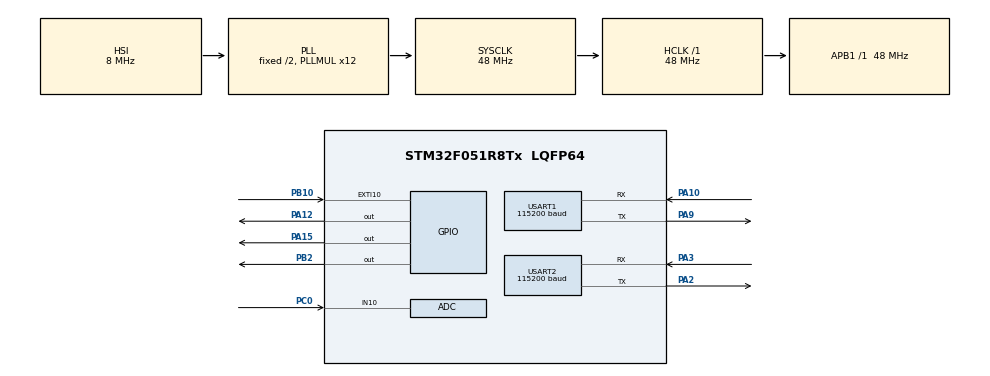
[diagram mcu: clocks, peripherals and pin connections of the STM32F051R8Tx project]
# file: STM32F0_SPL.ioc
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Mcu.Family=STM32F0
Mcu.Name=STM32F051R8Tx
Mcu.Package=LQFP64
NVIC.ADC1_COMP_IRQn=true\:0\:0\:false\:false\:true
NVIC.EXTI4_15_IRQn=true\:0\:0\:false\:false\:true
NVIC.TIM3_IRQn=true\:0\:0\:false\:false\:true
NVIC.USART1_IRQn=true\:0\:0\:false\:false\:true
NVIC.USART2_IRQn=true\:0\:0\:false\:false\:true
PA10.Mode=Asynchronous
PA10.Signal=USART1_RX
PA12.PinState=GPIO_PIN_SET
PA12.Signal=GPIO_Output
PA13.Mode=Serial-WireDebug
PA13.Signal=SYS_SWDIO
PA14.Mode=Serial-WireDebug
PA14.Signal=SYS_SWCLK
PA15.PinState=GPIO_PIN_SET
PA15.Signal=GPIO_Output
PA2.Mode=Asynchronous
PA2.Signal=USART2_TX
PA3.Mode=Asynchronous
PA3.Signal=USART2_RX
PA9.Mode=Asynchronous
PA9.Signal=USART1_TX
PB10.GPIO_ModeDefaultEXTI=GPIO_MODE_IT_FALLING
PB10.Signal=GPXTI10
PB2.Signal=GPIO_Output
PC0.Mode=IN10
PC0.Signal=ADC_IN10
ProjectManager.HeapSize=0x200
ProjectManager.StackSize=0x400
ProjectManager.TargetToolchain=MDK-ARM V5
RCC.AHBFreq_Value=48000000
RCC.APB1Freq_Value=48000000
RCC.APB1TimFreq_Value=48000000
RCC.HCLKFreq_Value=48000000
RCC.PLLMUL=RCC_PLL_MUL12
RCC.SYSCLKFreq_VALUE=48000000
RCC.SYSCLKSource=RCC_SYSCLKSOURCE_PLLCLK
USART1.BaudRate=115200
USART2.BaudRate=115200
VP_TIM3_VS_ClockSourceINT.Mode=Internal
board=STM32F0_SPL

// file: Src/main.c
/**
  ******************************************************************************
  * File Name          : main.c
  * Description        : Main program body
  ******************************************************************************
  *
  * COPYRIGHT(c) 2016 STMicroelectronics
  *
  * Redistribution and use in source and binary forms, with or without modification,
  * are permitted provided that the following conditions are met:
  *   1. Redistributions of source code must retain the above copyright notice,
  *      this list of conditions and the following disclaimer.
  *   2. Redistributions in binary form must reproduce the above copyright notice,
  *      this list of conditions and the following disclaimer in the documentation
  *      and/or other materials provided with the distribution.
  *   3. Neither the name of STMicroelectronics nor the names of its contributors
  *      may be used to endorse or promote products derived from this software
  *      without specific prior written permission.
  *
  * THIS SOFTWARE IS PROVIDED BY THE COPYRIGHT HOLDERS AND CONTRIBUTORS "AS IS"
  * AND ANY EXPRESS OR IMPLIED WARRANTIES, INCLUDING, BUT NOT LIMITED TO, THE
  * IMPLIED WARRANTIES OF MERCHANTABILITY AND FITNESS FOR A PARTICULAR PURPOSE ARE
  * DISCLAIMED. IN NO EVENT SHALL THE COPYRIGHT HOLDER OR CONTRIBUTORS BE LIABLE
  * FOR ANY DIRECT, INDIRECT, INCIDENTAL, SPECIAL, EXEMPLARY, OR CONSEQUENTIAL
  * DAMAGES (INCLUDING, BUT NOT LIMITED TO, PROCUREMENT OF SUBSTITUTE GOODS OR
  * SERVICES; LOSS OF USE, DATA, OR PROFITS; OR BUSINESS INTERRUPTION) HOWEVER
  * CAUSED AND ON ANY THEORY OF LIABILITY, WHETHER IN CONTRACT, STRICT LIABILITY,
  * OR TORT (INCLUDING NEGLIGENCE OR OTHERWISE) ARISING IN ANY WAY OUT OF THE USE
  * OF THIS SOFTWARE, EVEN IF ADVISED OF THE POSSIBILITY OF SUCH DAMAGE.
  *
  ******************************************************************************
  */
//#include "stm32f0xx_hal.h"
#include "main.h"
#include "print_debug.h"
#include "gsm.h"

#include "network.h"

ADC_HandleTypeDef hadc;

TIM_HandleTypeDef htim3;

UART_HandleTypeDef huart1;
UART_HandleTypeDef huart2;

/* USER CODE BEGIN PV */
/* Private variables ---------------------------------------------------------*/
data_t data_gsm, data_debug;
recv_uart_t recv_uart_1,recv_uart_2;
/* USER CODE END PV */

void SystemClock_Config(void);
static void MX_GPIO_Init(void);
static void MX_ADC_Init(void);
static void MX_TIM3_Init(void);
static void MX_USART1_UART_Init(void);
static void MX_USART2_UART_Init(void);

extern int FlagSendAlarm;

/* USER CODE BEGIN PFP */
/* Private function prototypes -----------------------------------------------*/

/* USER CODE END PFP */

int main(void)
{

  /* USER CODE BEGIN 1 */
	int8_t ret = 0;
	uint16_t idx_r = 0;
	char *tok = NULL;
	char *tok_buf = NULL;
  /* USER CODE END 1 */

  /* MCU Configuration----------------------------------------------------------*/

  /* Reset of all peripherals, Initializes the Flash interface and the Systick. */
  HAL_Init();

  /* Configure the system clock */
  SystemClock_Config();

  /* Initialize all configured peripherals */
  MX_GPIO_Init();
  MX_ADC_Init();
  MX_TIM3_Init();
  MX_USART1_UART_Init();
  MX_USART2_UART_Init();

	__HAL_UART_ENABLE_IT(&huart1,UART_IT_RXNE);
	__HAL_UART_ENABLE_IT(&huart2,UART_IT_RXNE);
	memset(&recv_uart_1,0,sizeof(recv_uart_t));
	memset(&recv_uart_2,0,sizeof(recv_uart_t));
	print_init(&huart2);

  /* Infinite loop */
  /* USER CODE BEGIN WHILE */

	memset(&data_gsm,0,sizeof(data_t));
	memset(&data_debug,0,sizeof(data_t));

//	HAL_GPIO_WritePin(GPIOC,GPIO_PIN_6,GPIO_PIN_SET);
//	HAL_Delay(1000);
//	HAL_GPIO_WritePin(GPIOC,GPIO_PIN_6,GPIO_PIN_RESET);
//	HAL_Delay(500);
//
//	HAL_GPIO_WritePin(GPIOA,GPIO_PIN_15,GPIO_PIN_RESET);
//	HAL_Delay(1000);
//	HAL_GPIO_WritePin(GPIOA,GPIO_PIN_12,GPIO_PIN_RESET);
//	HAL_Delay(1000);
//	HAL_GPIO_WritePin(GPIOA,GPIO_PIN_12,GPIO_PIN_SET);
//	HAL_Delay(1000);
//	HAL_GPIO_WritePin(GPIOA,GPIO_PIN_11,GPIO_PIN_RESET);
//	HAL_Delay(1000);
//
//	HAL_GPIO_WritePin(GPIOC,GPIO_PIN_6,GPIO_PIN_SET);
//	HAL_Delay(1000);
//	HAL_GPIO_WritePin(GPIOC,GPIO_PIN_6,GPIO_PIN_RESET);
//	HAL_Delay(500);

//	while(1){
//
//		ret = gsm_read(data_gsm.value,&data_gsm.length);
//		if(ret){
//			if(data_gsm.length > 0){
//				print_payload(0,data_gsm.value,data_gsm.length);
//			}
//		}
//		ret = uart2_read(data_debug.value,&data_debug.length,255);
//		if(ret){
//			if(data_debug.length > 0){
//				//print_payload(0,data_debug.value,data_debug.length);
//				gsm_write(data_debug.value,data_debug.length);
//			}
//		}
//	}
//
//	HAL_UART_Transmit(&huart1,(uint8_t*)"AT+CGPSPWR=1\r\n",14,100);
//	HAL_Delay(1000);
//	ret = gsm_read(data_gsm.value,&data_gsm.length);
//	if(ret){
//		if(data_gsm.length > 0){
//			HAL_UART_Transmit(&huart2,data_gsm.value,data_gsm.length,100);
//			print_payload(0,data_gsm.value,data_gsm.length);
//		}
//	}
//
//	HAL_UART_Transmit(&huart1,(uint8_t*)"AT+CGPSRST=0\r\n",14,100);
//	HAL_Delay(1000);
//	if(ret){
//		if(data_gsm.length > 0){
//			print_payload(0,data_gsm.value,data_gsm.length);
//		}
//	}
//
//	HAL_UART_Transmit(&huart1,(uint8_t*)"AT+CGPSSTATUS?\r\n",16,100);
//	HAL_Delay(1000);
//	if(ret){
//		if(data_gsm.length > 0){
//			print_payload(0,data_gsm.value,data_gsm.length);
//		}
//	}
	Power_On();
//	//HAL_Delay(10000);
	//Start_GPS();
	net_ptc(NET_MQTT_PTC);

	//power_onGPS();
	HAL_Delay(2000);

  while (1)
  {
  /* USER CODE END WHILE */

		HAL_Delay(1000);
		net_run();

		//read_sensor();

  }

}

void Power_On(void)
{
	uint8_t ret =0;
	print_debug(0,"program startup...\n");
	HAL_GPIO_WritePin(GPIOA,GPIO_PIN_15,GPIO_PIN_RESET);
	HAL_Delay(1000);
	HAL_GPIO_WritePin(GPIOA,GPIO_PIN_12,GPIO_PIN_RESET);
	HAL_Delay(3000);
	HAL_GPIO_WritePin(GPIOA,GPIO_PIN_12,GPIO_PIN_SET);

	HAL_GPIO_WritePin(GPIOA,GPIO_PIN_11,GPIO_PIN_RESET);

	HAL_Delay(5000);

	print_debug(0,"[GSM] AT \n");
	SsendATcommand((uint8_t*)"ATE0\r\n",4,(uint8_t*)"\r\nOK\r\n",6,500);
	while(ret==0)
	{
		ret = SsendATcommand((uint8_t*)"AT\r\n",4,(uint8_t*)"\r\nOK\r\n",6,500);
	}
	print_debug(0,"[INFO] GSM ON.\r\n");

	print_debug(0,"(Powers GPS)AT+CGPSPWR=1\r\n");
	SsendATcommand((uint8_t*)"AT+CGPSPWR=1\r\n",14,(uint8_t*)"\r\nOK\r\n",6,500);
	HAL_Delay(2000);

	print_debug(0,"(Set Reset mode)AT+CGPSRST=0\r\n");
	SsendATcommand((uint8_t*)"AT+CGPSRST=0\r\n",14,(uint8_t*)"\r\nOK\r\n",6,500);

	ReadBett();

	//ret = 0;
	while(1)
	{
		print_debug(0,"(STATUS)AT+CGPSSTATUS?\r\n");
		if(SsendATcommand((uint8_t*)"AT+CGPSSTATUS?\r\n",16,(uint8_t*)"\r\n+CGPSSTATUS: Location 2D Fix\r\n",32,5000))
		{
			break;
		}
		if(SsendATcommand((uint8_t*)"AT+CGPSSTATUS?\r\n",16,(uint8_t*)"\r\n+CGPSSTATUS: Location 3D Fix\r\n",32,5000))
		{
			break;
		}
	}

	while (SsendATcommand((uint8_t*)"AT+CREG?\r\n",14,(uint8_t*)"\r\n+CREG: 0,1",12,2000) == 0);

	print_debug(0,"[GSM] SET GPRS.\r\n");
	SsendATcommand((uint8_t*)"AT+SAPBR=3,1,\"Contype\",\"GPRS\"\r\n",31,(uint8_t*)"\r\nOK\r\n",6,500);
	print_debug(0,"[GSM] SET APN.\r\n");
	SsendATcommand((uint8_t*)"AT+SAPBR=3,1,\"APN\",\"www.dtac.co.th\"\r\n",37,(uint8_t*)"\r\nOK\r\n",6,500);

	 // gets the GPRS bearer
	print_debug(0,"[GSM] GET GPRS.\r\n");
	while (SsendATcommand((uint8_t*)"AT+SAPBR=1,1\r\n",14,(uint8_t*)"\r\nOK\r\n",6,3000) == 0)
	{
			//print_debug(0,"[GSM] ERROR\r\n");
			HAL_Delay(5000);
	}

}

int SsendATcommand(uint8_t* ATcommand,uint16_t lenAT,uint8_t* Ret,uint16_t lenRet,int Time)
{
	int ret =0;
	int C = 0;
	ret = gsm_write((uint8_t*)ATcommand,lenAT);
	HAL_Delay(Time);
	ret = gsm_read(data_gsm.value,&data_gsm.length);
	if(ret == 1)
	{
		if(data_gsm.length > 0){
			print_payload(0,data_gsm.value,data_gsm.length);
			//print_debug(0,"(RETURN GSM) %s  :",data_gsm.value);
			if(strncmp((char*)data_gsm.value,(char*)Ret,lenRet)==0){
				C = 1;
				//print_debug(0,"[INFO] GSM ON.\r\n");
				//print_debug(0,"[INFO] GSM ON.\r\n");
				//break;
			}
		}
	}

	return C;
}

/** System Clock Configuration
*/
void SystemClock_Config(void)
{

  RCC_OscInitTypeDef RCC_OscInitStruct;
  RCC_ClkInitTypeDef RCC_ClkInitStruct;
  RCC_PeriphCLKInitTypeDef PeriphClkInit;

  RCC_OscInitStruct.OscillatorType = RCC_OSCILLATORTYPE_HSI|RCC_OSCILLATORTYPE_HSI14;
  RCC_OscInitStruct.HSIState = RCC_HSI_ON;
  RCC_OscInitStruct.HSI14State = RCC_HSI14_ON;
  RCC_OscInitStruct.HSICalibrationValue = 16;
  RCC_OscInitStruct.HSI14CalibrationValue = 16;
  RCC_OscInitStruct.PLL.PLLState = RCC_PLL_ON;
  RCC_OscInitStruct.PLL.PLLSource = RCC_PLLSOURCE_HSI;
  RCC_OscInitStruct.PLL.PLLMUL = RCC_PLL_MUL12;
  RCC_OscInitStruct.PLL.PREDIV = RCC_PREDIV_DIV1;
  HAL_RCC_OscConfig(&RCC_OscInitStruct);

  RCC_ClkInitStruct.ClockType = RCC_CLOCKTYPE_HCLK|RCC_CLOCKTYPE_SYSCLK
                              |RCC_CLOCKTYPE_PCLK1;
  RCC_ClkInitStruct.SYSCLKSource = RCC_SYSCLKSOURCE_PLLCLK;
  RCC_ClkInitStruct.AHBCLKDivider = RCC_SYSCLK_DIV1;
  RCC_ClkInitStruct.APB1CLKDivider = RCC_HCLK_DIV1;
  HAL_RCC_ClockConfig(&RCC_ClkInitStruct, FLASH_LATENCY_1);

  PeriphClkInit.PeriphClockSelection = RCC_PERIPHCLK_USART1;
  PeriphClkInit.Usart1ClockSelection = RCC_USART1CLKSOURCE_PCLK1;
  HAL_RCCEx_PeriphCLKConfig(&PeriphClkInit);

  HAL_SYSTICK_Config(HAL_RCC_GetHCLKFreq()/1000);

  HAL_SYSTICK_CLKSourceConfig(SYSTICK_CLKSOURCE_HCLK);

  /* SysTick_IRQn interrupt configuration */
  HAL_NVIC_SetPriority(SysTick_IRQn, 0, 0);
}

/* ADC init function */
void MX_ADC_Init(void)
{

  ADC_ChannelConfTypeDef sConfig;

    /**Configure the global features of the ADC (Clock, Resolution, Data Alignment and number of conversion)
    */
  hadc.Instance = ADC1;
  hadc.Init.ClockPrescaler = ADC_CLOCK_ASYNC_DIV1;
  hadc.Init.Resolution = ADC_RESOLUTION_12B;
  hadc.Init.DataAlign = ADC_DATAALIGN_RIGHT;
  hadc.Init.ScanConvMode = ADC_SCAN_DIRECTION_FORWARD;
  hadc.Init.EOCSelection = ADC_EOC_SINGLE_CONV;
  hadc.Init.LowPowerAutoWait = DISABLE;
  hadc.Init.LowPowerAutoPowerOff = DISABLE;
  hadc.Init.ContinuousConvMode = DISABLE;
  hadc.Init.DiscontinuousConvMode = DISABLE;
  hadc.Init.ExternalTrigConvEdge = ADC_EXTERNALTRIGCONVEDGE_NONE;
  hadc.Init.DMAContinuousRequests = DISABLE;
  hadc.Init.Overrun = ADC_OVR_DATA_PRESERVED;
  HAL_ADC_Init(&hadc);

    /**Configure for the selected ADC regular channel to be converted.
    */
  sConfig.Channel = ADC_CHANNEL_10;
  sConfig.Rank = ADC_RANK_CHANNEL_NUMBER;
  sConfig.SamplingTime = ADC_SAMPLETIME_1CYCLE_5;
  HAL_ADC_ConfigChannel(&hadc, &sConfig);

}

/* TIM3 init function */
void MX_TIM3_Init(void)
{

  TIM_ClockConfigTypeDef sClockSourceConfig;
  TIM_MasterConfigTypeDef sMasterConfig;

  htim3.Instance = TIM3;
  htim3.Init.Prescaler = 0;
  htim3.Init.CounterMode = TIM_COUNTERMODE_UP;
  htim3.Init.Period = 0;
  htim3.Init.ClockDivision = TIM_CLOCKDIVISION_DIV1;
  HAL_TIM_Base_Init(&htim3);

  sClockSourceConfig.ClockSource = TIM_CLOCKSOURCE_INTERNAL;
  HAL_TIM_ConfigClockSource(&htim3, &sClockSourceConfig);

  sMasterConfig.MasterOutputTrigger = TIM_TRGO_RESET;
  sMasterConfig.MasterSlaveMode = TIM_MASTERSLAVEMODE_DISABLE;
  HAL_TIMEx_MasterConfigSynchronization(&htim3, &sMasterConfig);

}

/* USART1 init function */
void MX_USART1_UART_Init(void)
{

  huart1.Instance = USART1;
	huart1.Init.BaudRate = 9600;
  huart1.Init.WordLength = UART_WORDLENGTH_8B;
  huart1.Init.StopBits = UART_STOPBITS_1;
  huart1.Init.Parity = UART_PARITY_NONE;
  huart1.Init.Mode = UART_MODE_TX_RX;
  huart1.Init.HwFlowCtl = UART_HWCONTROL_NONE;
  huart1.Init.OverSampling = UART_OVERSAMPLING_16;
  huart1.Init.OneBitSampling = UART_ONE_BIT_SAMPLE_DISABLE;
  huart1.AdvancedInit.AdvFeatureInit = UART_ADVFEATURE_NO_INIT;
  HAL_UART_Init(&huart1);

}

/* USART2 init function */
void MX_USART2_UART_Init(void)
{

  huart2.Instance = USART2;
  huart2.Init.BaudRate = 115200;
  huart2.Init.WordLength = UART_WORDLENGTH_8B;
  huart2.Init.StopBits = UART_STOPBITS_1;
  huart2.Init.Parity = UART_PARITY_NONE;
  huart2.Init.Mode = UART_MODE_TX_RX;
  huart2.Init.HwFlowCtl = UART_HWCONTROL_NONE;
  huart2.Init.OverSampling = UART_OVERSAMPLING_16;
  huart2.Init.OneBitSampling = UART_ONE_BIT_SAMPLE_DISABLE;
  huart2.AdvancedInit.AdvFeatureInit = UART_ADVFEATURE_NO_INIT;
  HAL_UART_Init(&huart2);

}

/** Configure pins as
        * Analog
        * Input
        * Output
        * EVENT_OUT
        * EXTI
*/
void MX_GPIO_Init(void)
{

  GPIO_InitTypeDef GPIO_InitStruct;

  /* GPIO Ports Clock Enable */
  __HAL_RCC_GPIOC_CLK_ENABLE();
  __HAL_RCC_GPIOA_CLK_ENABLE();
  __HAL_RCC_GPIOB_CLK_ENABLE();

  /*Configure GPIO pin Output Level */
  HAL_GPIO_WritePin(GPIOB, GPIO_PIN_2, GPIO_PIN_RESET);

  /*Configure GPIO pin Output Level */
  HAL_GPIO_WritePin(GPIOA, GPIO_PIN_12|GPIO_PIN_15|GPIO_PIN_11, GPIO_PIN_SET);

  /*Configure GPIO pin : PB2 */
  GPIO_InitStruct.Pin = GPIO_PIN_2;
  GPIO_InitStruct.Mode = GPIO_MODE_OUTPUT_PP;
  GPIO_InitStruct.Pull = GPIO_NOPULL;
  GPIO_InitStruct.Speed = GPIO_SPEED_FREQ_LOW;
  HAL_GPIO_Init(GPIOB, &GPIO_InitStruct);

	/*Configure GPIO pin : PC6 */
	//LED Output
  GPIO_InitStruct.Pin = GPIO_PIN_6;
  GPIO_InitStruct.Mode = GPIO_MODE_OUTPUT_PP;
  GPIO_InitStruct.Pull = GPIO_NOPULL;
  GPIO_InitStruct.Speed = GPIO_SPEED_FREQ_LOW;
  HAL_GPIO_Init(GPIOC, &GPIO_InitStruct);

  /*Configure GPIO pin : PB10 */
  GPIO_InitStruct.Pin = GPIO_PIN_10;
	GPIO_InitStruct.Mode =GPIO_MODE_INPUT;
//  GPIO_InitStruct.Mode = GPIO_MODE_IT_FALLING;
  GPIO_InitStruct.Pull = GPIO_NOPULL;
  HAL_GPIO_Init(GPIOB, &GPIO_InitStruct);

	GPIO_InitStruct.Pin = GPIO_PIN_11;
	GPIO_InitStruct.Mode =GPIO_MODE_INPUT;
  GPIO_InitStruct.Pull = GPIO_NOPULL;
	GPIO_InitStruct.Speed = GPIO_SPEED_FREQ_LOW;
  HAL_GPIO_Init(GPIOB, &GPIO_InitStruct);

  /*Configure GPIO pins : PA12 PA15 */
  GPIO_InitStruct.Pin = GPIO_PIN_12|GPIO_PIN_15|GPIO_PIN_11;
  GPIO_InitStruct.Mode = GPIO_MODE_OUTPUT_PP;
  GPIO_InitStruct.Pull = GPIO_NOPULL;
  GPIO_InitStruct.Speed = GPIO_SPEED_FREQ_LOW;
  HAL_GPIO_Init(GPIOA, &GPIO_InitStruct);

	 /* EXTI interrupt init*/
//  HAL_NVIC_SetPriority(EXTI4_15_IRQn, 0, 0);
//  HAL_NVIC_EnableIRQ(EXTI4_15_IRQn);

}

/************************ (C) COPYRIGHT STMicroelectronics *****END OF FILE****/
